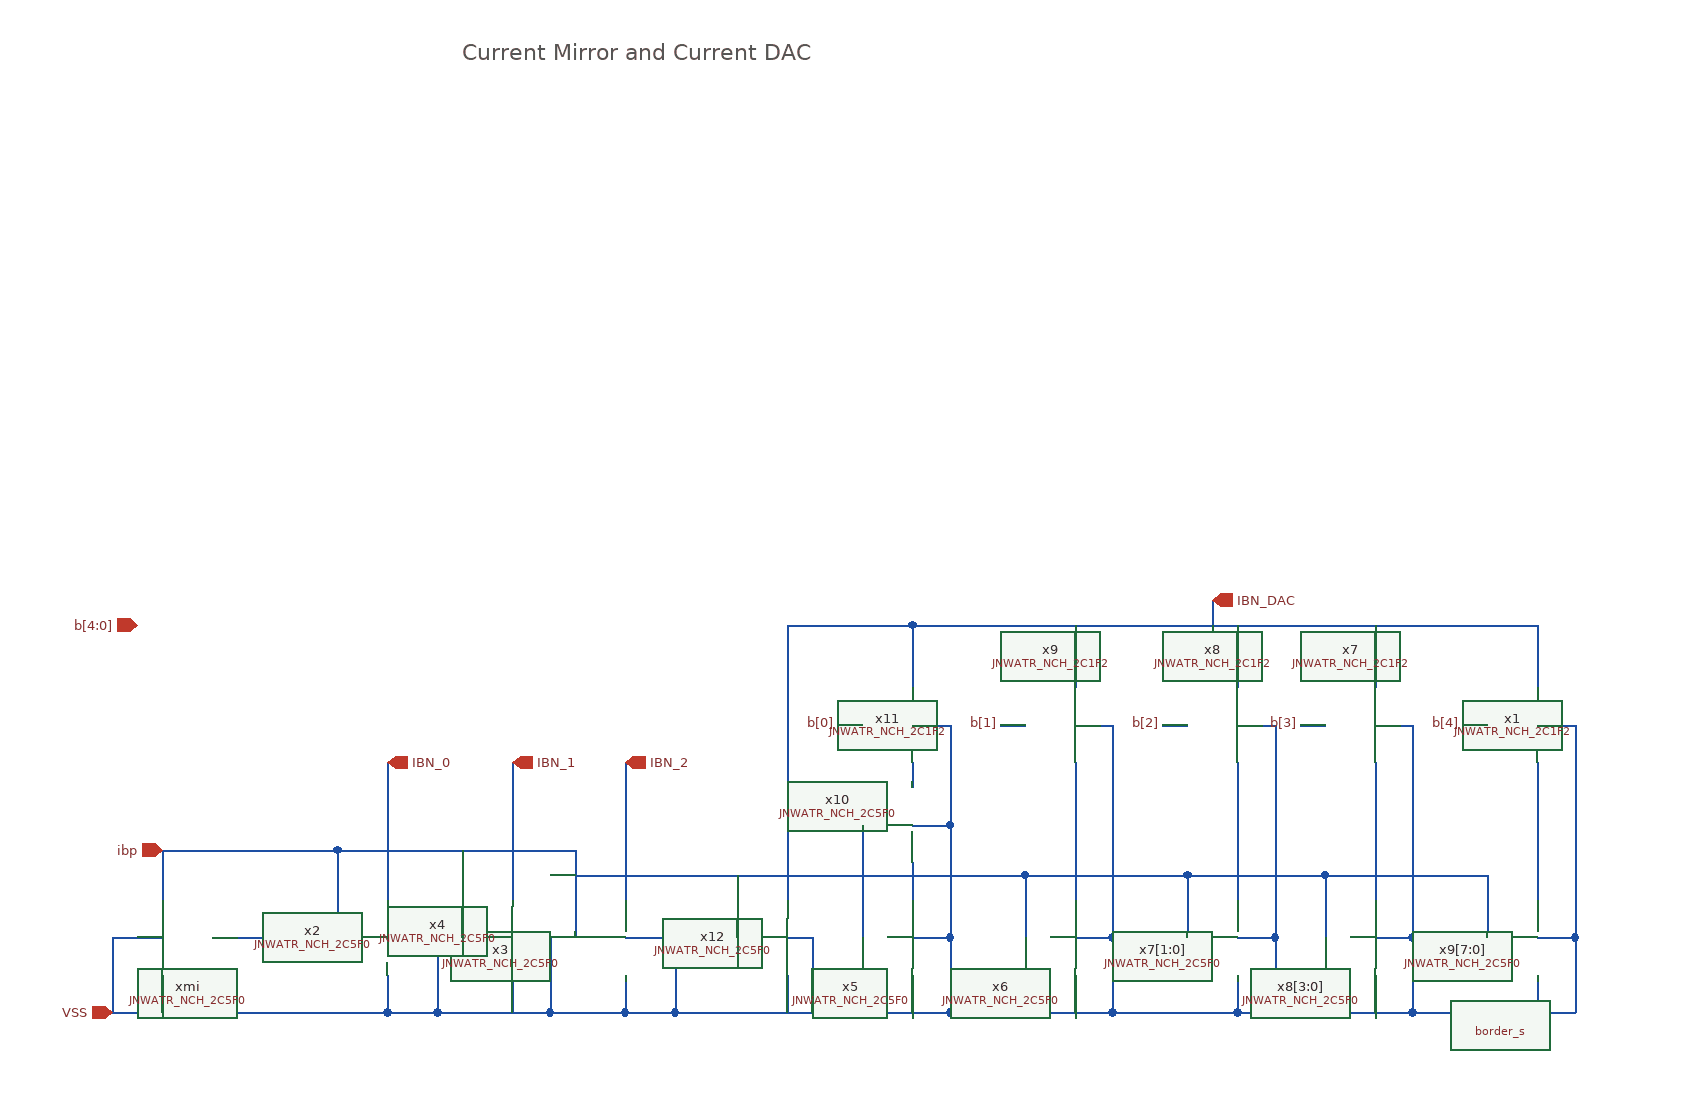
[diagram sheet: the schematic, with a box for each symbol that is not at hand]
v {xschem version=3.4.5 file_version=1.2
}
G {}
K {}
V {}
S {}
E {}
T {Current Mirror and Current DAC} 420 -960 0 0 1 1 {}
N 550 -240 590 -240 {
lab=VSS}
N 590 -240 590 -180 {
lab=VSS}
N 550 -180 590 -180 {
lab=VSS}
N 550 -210 550 -180 {
lab=VSS}
N 360 -240 400 -240 {
lab=VSS}
N 400 -240 400 -180 {
lab=VSS}
N 360 -180 400 -180 {
lab=VSS}
N 360 -210 360 -180 {
lab=VSS}
N 510 -310 510 -240 {
lab=ibp}
N 320 -310 510 -310 {
lab=ibp}
N 320 -310 320 -240 {
lab=ibp}
N 460 -240 490 -240 {
lab=VSS}
N 490 -240 490 -180 {
lab=VSS}
N 400 -180 490 -180 {
lab=VSS}
N 460 -210 460 -180 {
lab=VSS}
N 420 -310 420 -240 {
lab=ibp}
N 490 -180 550 -180 {
lab=VSS}
N 780 -240 810 -240 {
lab=VSS}
N 590 -180 810 -180 {
lab=VSS}
N 780 -330 810 -330 {
lab=VSS}
N 810 -330 810 -240 {
lab=VSS}
N 780 -300 780 -270 {
lab=#net1}
N 740 -330 740 -240 {
lab=ibp}
N 780 -210 780 -180 {
lab=VSS}
N 810 -240 810 -180 {
lab=VSS}
N 910 -240 940 -240 {
lab=VSS}
N 940 -240 940 -180 {
lab=VSS}
N 810 -180 940 -180 {
lab=VSS}
N 910 -210 910 -180 {
lab=VSS}
N 1040 -210 1040 -180 {
lab=VSS}
N 940 -180 1040 -180 {
lab=VSS}
N 1040 -240 1070 -240 {
lab=VSS}
N 1070 -240 1070 -180 {
lab=VSS}
N 1040 -180 1070 -180 {
lab=VSS}
N 1150 -240 1180 -240 {
lab=VSS}
N 1180 -240 1180 -180 {
lab=VSS}
N 1070 -180 1180 -180 {
lab=VSS}
N 1150 -210 1150 -180 {
lab=VSS}
N 1280 -210 1280 -180 {
lab=VSS}
N 1180 -180 1280 -180 {
lab=VSS}
N 1280 -240 1310 -240 {
lab=VSS}
N 1310 -240 1310 -180 {
lab=VSS}
N 1280 -180 1310 -180 {
lab=VSS}
N 780 -380 780 -360 {
lab=#net2}
N 780 -410 810 -410 {
lab=VSS}
N 810 -410 810 -330 {
lab=VSS}
N 910 -410 940 -410 {
lab=VSS}
N 940 -410 940 -240 {
lab=VSS}
N 1040 -410 1070 -410 {
lab=VSS}
N 1070 -410 1070 -240 {
lab=VSS}
N 1040 -380 1040 -270 {
lab=#net3}
N 1150 -380 1150 -270 {
lab=#net4}
N 1150 -410 1180 -410 {
lab=VSS}
N 1180 -410 1180 -240 {
lab=VSS}
N 1280 -410 1310 -410 {
lab=VSS}
N 1310 -410 1310 -240 {
lab=VSS}
N 1280 -380 1280 -270 {
lab=#net5}
N 870 -290 870 -240 {
lab=ibp}
N 510 -290 740 -290 {
lab=ibp}
N 740 -290 870 -290 {
lab=ibp}
N 870 -290 1000 -290 {
lab=ibp}
N 1000 -290 1000 -240 {
lab=ibp}
N 1000 -290 1110 -290 {
lab=ibp}
N 1110 -290 1110 -240 {
lab=ibp}
N 1110 -290 1240 -290 {
lab=ibp}
N 1240 -290 1240 -240 {
lab=ibp}
N 980 -410 1000 -410 {
lab=b[2]}
N 1090 -410 1110 -410 {
lab=b[3]}
N 1220 -410 1240 -410 {
lab=b[4]}
N 1280 -490 1280 -440 {
lab=IBN_DAC}
N 780 -490 1280 -490 {
lab=IBN_DAC}
N 780 -490 780 -440 {
lab=IBN_DAC}
N 910 -490 910 -440 {
lab=IBN_DAC}
N 1040 -490 1040 -440 {
lab=IBN_DAC}
N 1150 -490 1150 -440 {
lab=IBN_DAC}
N 910 -380 910 -270 {
lab=#net6}
N 850 -410 870 -410 {
lab=b[1]}
N 720 -410 740 -410 {
lab=b[0]}
N 140 -240 180 -240 {
lab=VSS}
N 140 -240 140 -180 {
lab=VSS}
N 140 -180 360 -180 {
lab=VSS}
N 180 -210 180 -180 {
lab=VSS}
N 220 -240 320 -240 {
lab=ibp}
N 180 -310 180 -270 {
lab=ibp}
N 180 -310 320 -310 {
lab=ibp}
N 360 -380 360 -270 {
lab=IBN_0}
N 460 -380 460 -270 {
lab=IBN_1}
N 550 -380 550 -270 {
lab=IBN_2}
N 1020 -510 1020 -490 {
lab=IBN_DAC}
N 680 -240 700 -240 {
lab=VSS}
N 700 -240 700 -180 {
lab=VSS}
N 680 -210 680 -180 {
lab=VSS}
N 680 -490 680 -360 {
lab=IBN_DAC}
N 680 -490 780 -490 {
lab=IBN_DAC}
N 640 -290 640 -240 {
lab=ibp}
N 680 -360 680 -270 {
lab=IBN_DAC}
C {devices/ipin.sym} 140 -180 0 0 {name=p2 lab=VSS}
C {devices/ipin.sym} 180 -310 0 0 {name=p3 lab=ibp

}
C {JNW_ATR_SKY130A/JNWATR_NCH_2C5F0.sym} 320 -240 0 0 {name=x2 }
C {JNW_ATR_SKY130A/JNWATR_NCH_2C5F0.sym} 510 -240 0 0 {name=x3 }
C {JNW_ATR_SKY130A/JNWATR_NCH_2C5F0.sym} 420 -240 0 0 {name=x4 }
C {JNW_ATR_SKY130A/JNWATR_NCH_2C5F0.sym} 740 -240 0 0 {name=x5 }
C {JNW_ATR_SKY130A/JNWATR_NCH_2C5F0.sym} 870 -240 0 0 {name=x6 }
C {JNW_ATR_SKY130A/JNWATR_NCH_2C5F0.sym} 1000 -240 0 0 {name=x7[1:0]}
C {JNW_ATR_SKY130A/JNWATR_NCH_2C5F0.sym} 1110 -240 0 0 {name=x8[3:0]}
C {JNW_ATR_SKY130A/JNWATR_NCH_2C5F0.sym} 1240 -240 0 0 {name=x9[7:0]}
C {JNW_ATR_SKY130A/JNWATR_NCH_2C5F0.sym} 740 -330 0 0 {name=x10 }
C {JNW_ATR_SKY130A/JNWATR_NCH_2C1F2.sym} 1240 -410 0 0 {name=x1 }
C {JNW_ATR_SKY130A/JNWATR_NCH_2C1F2.sym} 1110 -410 0 0 {name=x7 }
C {JNW_ATR_SKY130A/JNWATR_NCH_2C1F2.sym} 1000 -410 0 0 {name=x8 }
C {JNW_ATR_SKY130A/JNWATR_NCH_2C1F2.sym} 870 -410 0 0 {name=x9 }
C {JNW_ATR_SKY130A/JNWATR_NCH_2C1F2.sym} 740 -410 0 0 {name=x11 }
C {devices/lab_wire.sym} 980 -410 0 0 {name=p6 sig_type=std_logic lab=b[2]}
C {devices/lab_wire.sym} 1090 -410 0 0 {name=p7 sig_type=std_logic lab=b[3]}
C {devices/lab_wire.sym} 1220 -410 0 0 {name=p8 sig_type=std_logic lab=b[4]}
C {devices/lab_wire.sym} 850 -410 0 0 {name=p9 sig_type=std_logic lab=b[1]}
C {devices/lab_wire.sym} 720 -410 0 0 {name=p10 sig_type=std_logic lab=b[0]}
C {JNW_ATR_SKY130A/JNWATR_NCH_2C5F0.sym} 220 -240 0 1 {name=xmi}
C {devices/opin.sym} 360 -380 3 0 {name=p11 lab=IBN_0

}
C {devices/opin.sym} 460 -380 3 0 {name=p12 lab=IBN_1

}
C {devices/opin.sym} 550 -380 3 0 {name=p13 lab=IBN_2

}
C {devices/opin.sym} 1020 -510 3 0 {name=p14 lab=IBN_DAC

}
C {devices/ipin.sym} 160 -490 0 0 {name=p1 lab=b[4:0]

}
C {JNW_ATR_SKY130A/JNWATR_NCH_2C5F0.sym} 640 -240 0 0 {name=x12 }
C {cborder/border_s.sym} 1250 -170 0 0 {}
